VERSION 5.7 ;
  NOWIREEXTENSIONATPIN ON ;
  DIVIDERCHAR "/" ;
  BUSBITCHARS "[]" ;
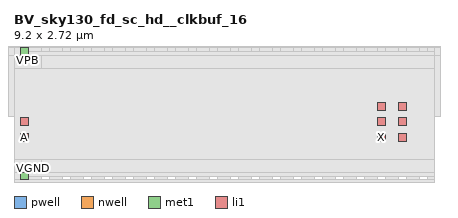
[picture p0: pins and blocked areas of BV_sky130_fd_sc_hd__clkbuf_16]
MACRO BV_sky130_fd_sc_hd__clkbuf_16
  CLASS BLOCK ;
  FOREIGN BV_sky130_fd_sc_hd__clkbuf_16 ;
  ORIGIN 0.000 0.000 ;
  SIZE 9.200 BY 2.720 ;
  PIN VNB
    PORT
      LAYER pwell ;
        RECT 0.145 -0.085 0.315 0.085 ;
    END
  END VNB
  PIN VPB
    PORT
      LAYER nwell ;
        RECT 0.145 2.635 0.315 2.805 ;
    END
  END VPB
  PIN VGND
    USE GROUND ;
    PORT
      LAYER met1 ;
        RECT 0.145 -0.085 0.315 0.085 ;
    END
  END VGND
  PIN VPWR
    USE POWER ;
    PORT
      LAYER met1 ;
        RECT 0.145 2.635 0.315 2.805 ;
    END
  END VPWR
  PIN A
    PORT
      LAYER li1 ;
        RECT 0.145 0.765 0.315 0.935 ;
    END
    PORT
      LAYER li1 ;
        RECT 0.145 1.105 0.315 1.275 ;
    END
  END A
  PIN X
    PORT
      LAYER li1 ;
        RECT 7.965 1.445 8.135 1.615 ;
    END
    PORT
      LAYER li1 ;
        RECT 8.425 1.445 8.595 1.615 ;
    END
    PORT
      LAYER li1 ;
        RECT 8.425 1.105 8.595 1.275 ;
    END
    PORT
      LAYER li1 ;
        RECT 7.965 1.105 8.135 1.275 ;
    END
    PORT
      LAYER li1 ;
        RECT 7.965 0.765 8.135 0.935 ;
    END
    PORT
      LAYER li1 ;
        RECT 8.425 0.765 8.595 0.935 ;
    END
  END X
  OBS
      LAYER nwell ;
        RECT -0.190 2.805 9.390 2.910 ;
        RECT -0.190 2.635 0.145 2.805 ;
        RECT 0.315 2.635 9.390 2.805 ;
        RECT -0.190 1.305 9.390 2.635 ;
        RECT 0.000 0.085 9.200 1.305 ;
      LAYER li1 ;
        RECT 0.000 2.720 0.145 2.805 ;
        RECT 0.315 2.720 0.605 2.805 ;
        RECT 0.775 2.720 1.065 2.805 ;
        RECT 1.235 2.720 1.525 2.805 ;
        RECT 1.695 2.720 1.985 2.805 ;
        RECT 2.155 2.720 2.445 2.805 ;
        RECT 2.615 2.720 2.905 2.805 ;
        RECT 3.075 2.720 3.365 2.805 ;
        RECT 3.535 2.720 3.825 2.805 ;
        RECT 3.995 2.720 4.285 2.805 ;
        RECT 4.455 2.720 4.745 2.805 ;
        RECT 4.915 2.720 5.205 2.805 ;
        RECT 5.375 2.720 5.665 2.805 ;
        RECT 5.835 2.720 6.125 2.805 ;
        RECT 6.295 2.720 6.585 2.805 ;
        RECT 6.755 2.720 7.045 2.805 ;
        RECT 7.215 2.720 7.505 2.805 ;
        RECT 7.675 2.720 7.965 2.805 ;
        RECT 8.135 2.720 8.425 2.805 ;
        RECT 8.595 2.720 8.885 2.805 ;
        RECT 9.055 2.720 9.200 2.805 ;
        RECT 0.000 1.785 9.200 2.720 ;
        RECT 0.000 1.445 7.795 1.785 ;
        RECT 0.485 0.595 7.795 1.445 ;
        RECT 8.765 0.595 9.200 1.785 ;
        RECT 0.000 0.000 9.200 0.595 ;
        RECT 0.000 -0.085 0.145 0.000 ;
        RECT 0.315 -0.085 0.605 0.000 ;
        RECT 0.775 -0.085 1.065 0.000 ;
        RECT 1.235 -0.085 1.525 0.000 ;
        RECT 1.695 -0.085 1.985 0.000 ;
        RECT 2.155 -0.085 2.445 0.000 ;
        RECT 2.615 -0.085 2.905 0.000 ;
        RECT 3.075 -0.085 3.365 0.000 ;
        RECT 3.535 -0.085 3.825 0.000 ;
        RECT 3.995 -0.085 4.285 0.000 ;
        RECT 4.455 -0.085 4.745 0.000 ;
        RECT 4.915 -0.085 5.205 0.000 ;
        RECT 5.375 -0.085 5.665 0.000 ;
        RECT 5.835 -0.085 6.125 0.000 ;
        RECT 6.295 -0.085 6.585 0.000 ;
        RECT 6.755 -0.085 7.045 0.000 ;
        RECT 7.215 -0.085 7.505 0.000 ;
        RECT 7.675 -0.085 7.965 0.000 ;
        RECT 8.135 -0.085 8.425 0.000 ;
        RECT 8.595 -0.085 8.885 0.000 ;
        RECT 9.055 -0.085 9.200 0.000 ;
      LAYER met1 ;
        RECT 0.000 2.805 9.200 2.960 ;
        RECT 0.000 2.635 0.145 2.805 ;
        RECT 0.315 2.720 0.605 2.805 ;
        RECT 0.775 2.720 1.065 2.805 ;
        RECT 1.235 2.720 1.525 2.805 ;
        RECT 1.695 2.720 1.985 2.805 ;
        RECT 2.155 2.720 2.445 2.805 ;
        RECT 2.615 2.720 2.905 2.805 ;
        RECT 3.075 2.720 3.365 2.805 ;
        RECT 3.535 2.720 3.825 2.805 ;
        RECT 3.995 2.720 4.285 2.805 ;
        RECT 4.455 2.720 4.745 2.805 ;
        RECT 4.915 2.720 5.205 2.805 ;
        RECT 5.375 2.720 5.665 2.805 ;
        RECT 5.835 2.720 6.125 2.805 ;
        RECT 6.295 2.720 6.585 2.805 ;
        RECT 6.755 2.720 7.045 2.805 ;
        RECT 7.215 2.720 7.505 2.805 ;
        RECT 7.675 2.720 7.965 2.805 ;
        RECT 8.135 2.720 8.425 2.805 ;
        RECT 8.595 2.720 8.885 2.805 ;
        RECT 9.055 2.720 9.200 2.805 ;
        RECT 0.315 2.635 9.200 2.720 ;
        RECT 0.595 2.355 9.200 2.635 ;
        RECT 0.000 0.365 9.200 2.355 ;
        RECT 0.595 0.085 9.200 0.365 ;
        RECT 0.000 -0.085 0.145 0.085 ;
        RECT 0.315 0.000 9.200 0.085 ;
        RECT 0.315 -0.085 0.605 0.000 ;
        RECT 0.775 -0.085 1.065 0.000 ;
        RECT 1.235 -0.085 1.525 0.000 ;
        RECT 1.695 -0.085 1.985 0.000 ;
        RECT 2.155 -0.085 2.445 0.000 ;
        RECT 2.615 -0.085 2.905 0.000 ;
        RECT 3.075 -0.085 3.365 0.000 ;
        RECT 3.535 -0.085 3.825 0.000 ;
        RECT 3.995 -0.085 4.285 0.000 ;
        RECT 4.455 -0.085 4.745 0.000 ;
        RECT 4.915 -0.085 5.205 0.000 ;
        RECT 5.375 -0.085 5.665 0.000 ;
        RECT 5.835 -0.085 6.125 0.000 ;
        RECT 6.295 -0.085 6.585 0.000 ;
        RECT 6.755 -0.085 7.045 0.000 ;
        RECT 7.215 -0.085 7.505 0.000 ;
        RECT 7.675 -0.085 7.965 0.000 ;
        RECT 8.135 -0.085 8.425 0.000 ;
        RECT 8.595 -0.085 8.885 0.000 ;
        RECT 9.055 -0.085 9.200 0.000 ;
        RECT 0.000 -0.240 9.200 -0.085 ;
  END
END BV_sky130_fd_sc_hd__clkbuf_16
END LIBRARY

